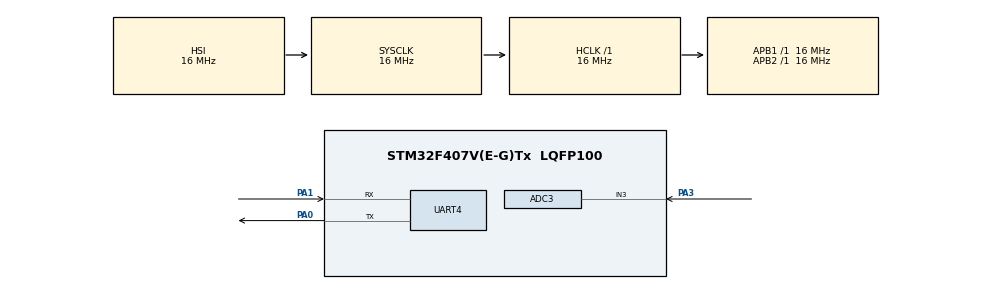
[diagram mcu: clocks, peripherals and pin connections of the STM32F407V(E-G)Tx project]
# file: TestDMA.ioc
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ADC3.Channel-1\#ChannelRegularConversion=ADC_CHANNEL_3
ADC3.ContinuousConvMode=ENABLE
ADC3.DMAContinuousRequests=ENABLE
ADC3.NbrOfConversionFlag=1
ADC3.Rank-1\#ChannelRegularConversion=1
ADC3.SamplingTime-1\#ChannelRegularConversion=ADC_SAMPLETIME_3CYCLES
Dma.ADC3.0.Direction=DMA_PERIPH_TO_MEMORY
Dma.ADC3.0.FIFOMode=DMA_FIFOMODE_DISABLE
Dma.ADC3.0.Instance=DMA2_Stream0
Dma.ADC3.0.MemDataAlignment=DMA_MDATAALIGN_HALFWORD
Dma.ADC3.0.MemInc=DMA_MINC_ENABLE
Dma.ADC3.0.Mode=DMA_CIRCULAR
Dma.ADC3.0.PeriphDataAlignment=DMA_PDATAALIGN_HALFWORD
Dma.ADC3.0.PeriphInc=DMA_PINC_DISABLE
Dma.ADC3.0.Priority=DMA_PRIORITY_LOW
Dma.Request0=ADC3
Dma.Request1=UART4_RX
Dma.Request2=UART4_TX
Dma.UART4_RX.1.Direction=DMA_PERIPH_TO_MEMORY
Dma.UART4_RX.1.FIFOMode=DMA_FIFOMODE_DISABLE
Dma.UART4_RX.1.Instance=DMA1_Stream2
Dma.UART4_RX.1.MemDataAlignment=DMA_MDATAALIGN_BYTE
Dma.UART4_RX.1.MemInc=DMA_MINC_ENABLE
Dma.UART4_RX.1.Mode=DMA_CIRCULAR
Dma.UART4_RX.1.PeriphDataAlignment=DMA_PDATAALIGN_BYTE
Dma.UART4_RX.1.PeriphInc=DMA_PINC_DISABLE
Dma.UART4_RX.1.Priority=DMA_PRIORITY_LOW
Dma.UART4_TX.2.Direction=DMA_MEMORY_TO_PERIPH
Dma.UART4_TX.2.FIFOMode=DMA_FIFOMODE_DISABLE
Dma.UART4_TX.2.Instance=DMA1_Stream4
Dma.UART4_TX.2.MemDataAlignment=DMA_MDATAALIGN_BYTE
Dma.UART4_TX.2.MemInc=DMA_MINC_ENABLE
Dma.UART4_TX.2.Mode=DMA_NORMAL
Dma.UART4_TX.2.PeriphDataAlignment=DMA_PDATAALIGN_BYTE
Dma.UART4_TX.2.PeriphInc=DMA_PINC_DISABLE
Dma.UART4_TX.2.Priority=DMA_PRIORITY_LOW
Mcu.Family=STM32F4
Mcu.Name=STM32F407V(E-G)Tx
Mcu.Package=LQFP100
NVIC.DMA1_Stream2_IRQn=true\:1\:0\:true\:false\:true\:false\:true
NVIC.DMA1_Stream4_IRQn=true\:1\:0\:true\:false\:true\:false\:true
NVIC.DMA2_Stream0_IRQn=true\:2\:0\:true\:false\:true\:false\:true
NVIC.PriorityGroup=NVIC_PRIORITYGROUP_4
NVIC.UART4_IRQn=true\:1\:0\:true\:false\:true\:true\:true
PA0-WKUP.Mode=Asynchronous
PA0-WKUP.Signal=UART4_TX
PA1.Mode=Asynchronous
PA1.Signal=UART4_RX
PA13.Mode=Serial_Wire
PA13.Signal=SYS_JTMS-SWDIO
PA14.Mode=Serial_Wire
PA14.Signal=SYS_JTCK-SWCLK
PA3.Signal=ADCx_IN3
PH0-OSC_IN.Mode=HSE-External-Oscillator
PH0-OSC_IN.Signal=RCC_OSC_IN
PH1-OSC_OUT.Mode=HSE-External-Oscillator
PH1-OSC_OUT.Signal=RCC_OSC_OUT
ProjectManager.HeapSize=0x200
ProjectManager.StackSize=0x400
ProjectManager.TargetToolchain=MDK-ARM V5
RCC.AHBFreq_Value=16000000
RCC.APB1Freq_Value=16000000
RCC.APB2Freq_Value=16000000
RCC.CortexFreq_Value=16000000
RCC.HSE_VALUE=25000000
RCC.HSI_VALUE=16000000
RCC.LSE_VALUE=32768
RCC.SYSCLKFreq_VALUE=16000000
RCC.VCOOutputFreq_Value=192000000
SH.ADCx_IN3.0=ADC3_IN3,IN3
UART4.VirtualMode=Asynchronous
board=custom

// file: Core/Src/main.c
/* USER CODE BEGIN Header */
/**
  ******************************************************************************
  * @file           : main.c
  * @brief          : Main program body
  ******************************************************************************
  * @attention
  *
  * <h2><center>&copy; Copyright (c) 2021 STMicroelectronics.
  * All rights reserved.</center></h2>
  *
  * This software component is licensed by ST under BSD 3-Clause license,
  * the "License"; You may not use this file except in compliance with the
  * License. You may obtain a copy of the License at:
  *                        opensource.org/licenses/BSD-3-Clause
  *
  ******************************************************************************
  */
/* USER CODE END Header */
#include "main.h"

ADC_HandleTypeDef hadc3;
DMA_HandleTypeDef hdma_adc3;

UART_HandleTypeDef huart4;
DMA_HandleTypeDef hdma_uart4_rx;
DMA_HandleTypeDef hdma_uart4_tx;

/* USER CODE BEGIN PV */
uint8_t transmitdata[5];
uint8_t receivedata;
uint16_t dmaread;
/* USER CODE END PV */

void SystemClock_Config(void);
static void MX_GPIO_Init(void);
static void MX_DMA_Init(void);
static void MX_UART4_Init(void);
static void MX_ADC3_Init(void);
/* USER CODE BEGIN PFP */
void num2str(int num);
/* USER CODE END PFP */

int main(void)
{

  /* MCU Configuration--------------------------------------------------------*/

  /* Reset of all peripherals, Initializes the Flash interface and the Systick. */
  HAL_Init();

  /* Configure the system clock */
  SystemClock_Config();

  /* Initialize all configured peripherals */
  MX_GPIO_Init();
  MX_DMA_Init();
  MX_UART4_Init();
  MX_ADC3_Init();
  /* USER CODE BEGIN 2 */
	HAL_UART_Receive_DMA(&huart4, &receivedata, 1);
	num2str(1234);
	HAL_UART_Transmit_DMA(&huart4, transmitdata, 5);
	HAL_ADC_Start_DMA(&hadc3, (uint32_t*) &dmaread, 1);

  /* USER CODE END 2 */

  /* Infinite loop */
  while (1)
  {
		num2str(dmaread);
		HAL_UART_Transmit_DMA(&huart4, transmitdata, 5);
		HAL_Delay(1000);
  }
}

void SystemClock_Config(void)
{
  RCC_OscInitTypeDef RCC_OscInitStruct = {0};
  RCC_ClkInitTypeDef RCC_ClkInitStruct = {0};

  /** Configure the main internal regulator output voltage
  */
  __HAL_RCC_PWR_CLK_ENABLE();
  __HAL_PWR_VOLTAGESCALING_CONFIG(PWR_REGULATOR_VOLTAGE_SCALE1);
  /** Initializes the RCC Oscillators according to the specified parameters
  * in the RCC_OscInitTypeDef structure.
  */
  RCC_OscInitStruct.OscillatorType = RCC_OSCILLATORTYPE_HSI;
  RCC_OscInitStruct.HSIState = RCC_HSI_ON;
  RCC_OscInitStruct.HSICalibrationValue = RCC_HSICALIBRATION_DEFAULT;
  RCC_OscInitStruct.PLL.PLLState = RCC_PLL_NONE;
  if (HAL_RCC_OscConfig(&RCC_OscInitStruct) != HAL_OK)
  {
    Error_Handler();
  }
  /** Initializes the CPU, AHB and APB buses clocks
  */
  RCC_ClkInitStruct.ClockType = RCC_CLOCKTYPE_HCLK|RCC_CLOCKTYPE_SYSCLK
                              |RCC_CLOCKTYPE_PCLK1|RCC_CLOCKTYPE_PCLK2;
  RCC_ClkInitStruct.SYSCLKSource = RCC_SYSCLKSOURCE_HSI;
  RCC_ClkInitStruct.AHBCLKDivider = RCC_SYSCLK_DIV1;
  RCC_ClkInitStruct.APB1CLKDivider = RCC_HCLK_DIV1;
  RCC_ClkInitStruct.APB2CLKDivider = RCC_HCLK_DIV1;

  if (HAL_RCC_ClockConfig(&RCC_ClkInitStruct, FLASH_LATENCY_0) != HAL_OK)
  {
    Error_Handler();
  }
}

static void MX_ADC3_Init(void)
{

  ADC_ChannelConfTypeDef sConfig = {0};

  /** Configure the global features of the ADC (Clock, Resolution, Data Alignment and number of conversion)
  */
  hadc3.Instance = ADC3;
  hadc3.Init.ClockPrescaler = ADC_CLOCK_SYNC_PCLK_DIV8;
  hadc3.Init.Resolution = ADC_RESOLUTION_12B;
  hadc3.Init.ScanConvMode = DISABLE;
  hadc3.Init.ContinuousConvMode = ENABLE;
  hadc3.Init.DiscontinuousConvMode = DISABLE;
  hadc3.Init.ExternalTrigConvEdge = ADC_EXTERNALTRIGCONVEDGE_NONE;
  hadc3.Init.ExternalTrigConv = ADC_EXTERNALTRIGCONV_T1_CC1 ;
  hadc3.Init.DataAlign = ADC_DATAALIGN_RIGHT;
  hadc3.Init.NbrOfConversion = 1;
  hadc3.Init.DMAContinuousRequests = ENABLE;
  hadc3.Init.EOCSelection = ADC_EOC_SINGLE_CONV;
  if (HAL_ADC_Init(&hadc3) != HAL_OK)
  {
    Error_Handler();
  }
  /** Configure for the selected ADC regular channel its corresponding rank in the sequencer and its sample time.
  */
  sConfig.Channel = ADC_CHANNEL_3;
  sConfig.Rank = 1;
  sConfig.SamplingTime = ADC_SAMPLETIME_15CYCLES;
  if (HAL_ADC_ConfigChannel(&hadc3, &sConfig) != HAL_OK)
  {
    Error_Handler();
  }

}

static void MX_UART4_Init(void)
{

  huart4.Instance = UART4;
  huart4.Init.BaudRate = 115200;
  huart4.Init.WordLength = UART_WORDLENGTH_8B;
  huart4.Init.StopBits = UART_STOPBITS_1;
  huart4.Init.Parity = UART_PARITY_NONE;
  huart4.Init.Mode = UART_MODE_TX_RX;
  huart4.Init.HwFlowCtl = UART_HWCONTROL_NONE;
  huart4.Init.OverSampling = UART_OVERSAMPLING_16;
  if (HAL_UART_Init(&huart4) != HAL_OK)
  {
    Error_Handler();
  }

}

static void MX_DMA_Init(void)
{

  /* DMA controller clock enable */
  __HAL_RCC_DMA2_CLK_ENABLE();
  __HAL_RCC_DMA1_CLK_ENABLE();

  /* DMA interrupt init */
  /* DMA1_Stream2_IRQn interrupt configuration */
  HAL_NVIC_SetPriority(DMA1_Stream2_IRQn, 0, 0);
  HAL_NVIC_EnableIRQ(DMA1_Stream2_IRQn);
  /* DMA1_Stream4_IRQn interrupt configuration */
  HAL_NVIC_SetPriority(DMA1_Stream4_IRQn, 0, 0);
  HAL_NVIC_EnableIRQ(DMA1_Stream4_IRQn);
  /* DMA2_Stream0_IRQn interrupt configuration */
  HAL_NVIC_SetPriority(DMA2_Stream0_IRQn, 1, 0);
  HAL_NVIC_EnableIRQ(DMA2_Stream0_IRQn);

}

static void MX_GPIO_Init(void)
{
  GPIO_InitTypeDef GPIO_InitStruct = {0};
  /* GPIO Ports Clock Enable */
  __HAL_RCC_GPIOH_CLK_ENABLE();
  __HAL_RCC_GPIOA_CLK_ENABLE();
  __HAL_RCC_GPIOD_CLK_ENABLE();

  /*Configure GPIO pin Output Level */
  HAL_GPIO_WritePin(GPIOD, LED1_Pin|LED2_Pin|LED3_Pin|LED4_Pin, GPIO_PIN_RESET);

  /*Configure GPIO pins : LED1_Pin LED2_Pin LED3_Pin LED4_Pin */
  GPIO_InitStruct.Pin = LED1_Pin|LED2_Pin|LED3_Pin|LED4_Pin;
  GPIO_InitStruct.Mode = GPIO_MODE_OUTPUT_PP;
  GPIO_InitStruct.Pull = GPIO_NOPULL;
  GPIO_InitStruct.Speed = GPIO_SPEED_FREQ_LOW;
  HAL_GPIO_Init(GPIOD, &GPIO_InitStruct);
}

/* USER CODE BEGIN 4 */
void HAL_UART_TxCpltCallback(UART_HandleTypeDef *huart)
{
	__nop();//HAL_GPIO_TogglePin(GPIOD, LED1_Pin);
}
void num2str(int num)
{
	transmitdata[4] = num%10  + 0x30;
	num = num/10;
	transmitdata[3] = num%10 + 0x30;
	num = num/10;
	transmitdata[2] = num%10 + 0x30;
	num = num/10;
	transmitdata[1] = num%10 + 0x30;
	transmitdata[0] = num/10 + 0x30;
}
void HAL_UART_RxCpltCallback(UART_HandleTypeDef *huart)
{
	//HAL_UART_Receive_DMA(&huart4, &receivedata, 1);
	switch(receivedata)
	{
		case 'A':
				HAL_GPIO_WritePin(GPIOD, LED1_Pin, GPIO_PIN_SET);
				HAL_GPIO_WritePin(GPIOD, LED2_Pin, GPIO_PIN_RESET);
				HAL_GPIO_WritePin(GPIOD, LED3_Pin, GPIO_PIN_RESET);
				HAL_GPIO_WritePin(GPIOD, LED4_Pin, GPIO_PIN_RESET);
		break;
		case 'B':
				HAL_GPIO_WritePin(GPIOD, LED2_Pin, GPIO_PIN_SET);
				HAL_GPIO_WritePin(GPIOD, LED1_Pin, GPIO_PIN_RESET);
				HAL_GPIO_WritePin(GPIOD, LED3_Pin, GPIO_PIN_RESET);
				HAL_GPIO_WritePin(GPIOD, LED4_Pin, GPIO_PIN_RESET);
		break;
		case 'C':
				HAL_GPIO_WritePin(GPIOD, LED3_Pin, GPIO_PIN_SET);
				HAL_GPIO_WritePin(GPIOD, LED2_Pin, GPIO_PIN_RESET);
				HAL_GPIO_WritePin(GPIOD, LED1_Pin, GPIO_PIN_RESET);
				HAL_GPIO_WritePin(GPIOD, LED4_Pin, GPIO_PIN_RESET);
		break;
		case 'D':
				HAL_GPIO_WritePin(GPIOD, LED4_Pin, GPIO_PIN_SET);
				HAL_GPIO_WritePin(GPIOD, LED2_Pin, GPIO_PIN_RESET);
				HAL_GPIO_WritePin(GPIOD, LED3_Pin, GPIO_PIN_RESET);
				HAL_GPIO_WritePin(GPIOD, LED1_Pin, GPIO_PIN_RESET);
		break;
		default:
				HAL_GPIO_WritePin(GPIOD, LED4_Pin, GPIO_PIN_RESET);
				HAL_GPIO_WritePin(GPIOD, LED2_Pin, GPIO_PIN_RESET);
				HAL_GPIO_WritePin(GPIOD, LED3_Pin, GPIO_PIN_RESET);
				HAL_GPIO_WritePin(GPIOD, LED1_Pin, GPIO_PIN_RESET);
		break;
	}
}

/* USER CODE END 4 */

void Error_Handler(void)
{
  __disable_irq();
  while (1)
  {
  }
}

/************************ (C) COPYRIGHT STMicroelectronics *****END OF FILE****/
